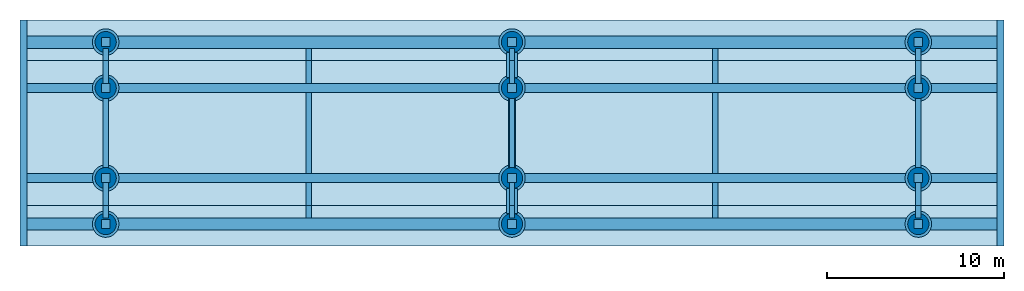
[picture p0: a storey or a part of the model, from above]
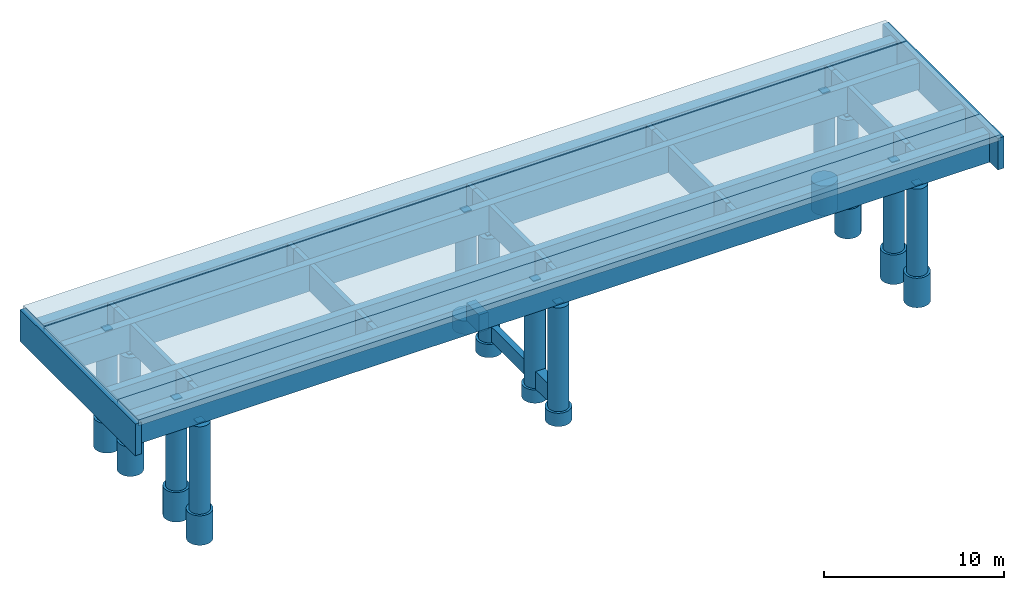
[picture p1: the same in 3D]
Properties of the parts of a building model (IFC2X3)

# File
Description: ViewDefinition [CoordinationView_V2.0]
Time: 2026-02-21T13:28:55
Written by: v1
Made in: SCIA Engineer 26.0.2015

# IfcBeam (3)
In: Building
Pset_BeamCommon - Slope: 0 rad; IsExternal: no; LoadBearing: yes; Span: 1000 mm
Name | Material
B34 | C30
B35 | C20
B36 | C20

# IfcColumn (12)
In: Building
Material: C30
Pset_ColumnCommon - Slope: 0 rad; IsExternal: no; LoadBearing: yes
Name
B1
B6
B7
B9
B11
B12
B16
B22
B23
B24
B30
B33

# IfcMember: member (53)
In: Building
Material: C30
Pset_MemberCommon - Slope: 0 rad; IsExternal: no; LoadBearing: yes; Span: 1000 mm
Name
B2
B3
B4
B5
B18
B20
B26
B27
B28
B29
B31
B32
B37
B38
B39
B40
B41
B42
B43
B44
B45
B46
B47
B48
B49
B50
B51
B52
B53
B54
B55
B56
B57
B58
B59
B60
B61
B62
B63
B64
B65
B66
B67
B68
B69
B70
B71
B72
B73
B74
B75
B76
B77

# IfcSlab (5)
In: Building
PredefinedType: FLOOR; Material: C30
Pset_SlabCommon - Combustible: no; ThermalTransmittance: 0 W/m2/K; IsExternal: no; LoadBearing: yes; Compartmentation: no; PitchAngle: 0 rad
Name
S4
S5
S6
S7
S8
